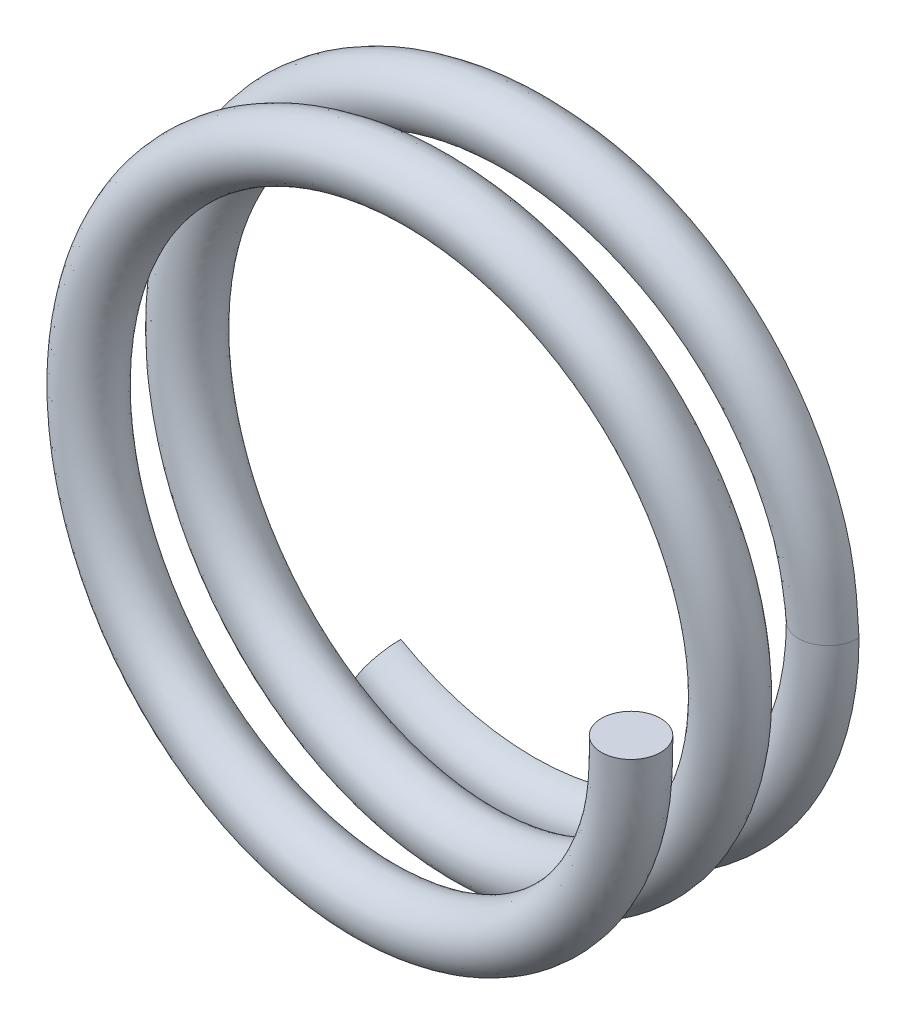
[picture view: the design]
ISO-10303-21;
HEADER;
FILE_DESCRIPTION(('STEP AP214'),'2;1');
FILE_NAME('part.step','',(''),(''),'','','');
FILE_SCHEMA(('AUTOMOTIVE_DESIGN { 1 0 10303 214 1 1 1 1 }'));
ENDSEC;
DATA;
#1=APPLICATION_CONTEXT('core data for automotive mechanical design processes');
#2=APPLICATION_PROTOCOL_DEFINITION('international standard','automotive_design',2000,#1);
#3=PRODUCT_CONTEXT('',#1,'mechanical');
#4=PRODUCT('Part','Part','',(#3));
#5=PRODUCT_RELATED_PRODUCT_CATEGORY('part','',(#4));
#6=PRODUCT_DEFINITION_FORMATION('','',#4);
#7=PRODUCT_DEFINITION_CONTEXT('part definition',#1,'design');
#8=PRODUCT_DEFINITION('design','',#6,#7);
#9=PRODUCT_DEFINITION_SHAPE('','',#8);
#10=(LENGTH_UNIT() NAMED_UNIT(*) SI_UNIT(.MILLI.,.METRE.));
#11=(NAMED_UNIT(*) PLANE_ANGLE_UNIT() SI_UNIT($,.RADIAN.));
#12=(NAMED_UNIT(*) SI_UNIT($,.STERADIAN.) SOLID_ANGLE_UNIT());
#13=UNCERTAINTY_MEASURE_WITH_UNIT(LENGTH_MEASURE(1.E-05),#10,'distance_accuracy_value','');
#14=(GEOMETRIC_REPRESENTATION_CONTEXT(3) GLOBAL_UNCERTAINTY_ASSIGNED_CONTEXT((#13)) GLOBAL_UNIT_ASSIGNED_CONTEXT((#10,
#11,#12)) REPRESENTATION_CONTEXT('',''));
#15=CARTESIAN_POINT('',(0.,0.,0.));
#16=DIRECTION('',(0.,0.,1.));
#17=DIRECTION('',(1.,0.,0.));
#18=AXIS2_PLACEMENT_3D('',#15,#16,#17);
#19=CARTESIAN_POINT('',(15.,0.,1.5));
#20=CARTESIAN_POINT('',(14.9434686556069,0.980039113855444,1.55199637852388));
#21=CARTESIAN_POINT('',(14.8302225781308,2.94329660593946,1.65615781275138));
#22=CARTESIAN_POINT('',(13.9418455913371,5.77650274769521,1.81245356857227));
#23=CARTESIAN_POINT('',(12.5535226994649,8.38759891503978,1.96879275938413));
#24=CARTESIAN_POINT('',(10.4671696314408,10.9271623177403,2.14223062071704));
#25=CARTESIAN_POINT('',(7.58613571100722,13.1398555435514,2.33334011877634));
#26=CARTESIAN_POINT('',(3.92662071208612,14.6543917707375,2.54166504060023));
#27=CARTESIAN_POINT('',(4.11401899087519E-05,15.1715918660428,2.75000784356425));
#28=CARTESIAN_POINT('',(-3.92693257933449,14.6556022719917,2.95833111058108));
#29=CARTESIAN_POINT('',(-7.58586251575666,13.1389788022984,3.1666585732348));
#30=CARTESIAN_POINT('',(-10.7277085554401,10.7277374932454,3.37500627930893));
#31=CARTESIAN_POINT('',(-13.1395863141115,7.58619905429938,3.58333901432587));
#32=CARTESIAN_POINT('',(-14.6551693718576,3.92680798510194,3.79165669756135));
#33=CARTESIAN_POINT('',(-15.1712462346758,-3.12971002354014E-05,3.99999979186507));
#34=CARTESIAN_POINT('',(-14.6548300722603,-3.92669076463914,4.20834340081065));
#35=CARTESIAN_POINT('',(-13.1398206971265,-7.58627068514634,4.41666146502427));
#36=CARTESIAN_POINT('',(-10.7278130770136,-10.7278977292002,4.62499295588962));
#37=CARTESIAN_POINT('',(-7.58571450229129,-13.1387744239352,4.83334182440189));
#38=CARTESIAN_POINT('',(-3.92696085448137,-14.6554610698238,5.04166963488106));
#39=CARTESIAN_POINT('',(4.36291658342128E-05,-15.1719571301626,5.24998976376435));
#40=CARTESIAN_POINT('',(3.92661725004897,-14.6542791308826,5.45833563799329));
#41=CARTESIAN_POINT('',(7.5859316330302,-13.1393329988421,5.66667583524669));
#42=CARTESIAN_POINT('',(10.7285480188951,-10.7285399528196,5.87499262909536));
#43=CARTESIAN_POINT('',(13.1388208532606,-7.58563797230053,6.08332834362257));
#44=CARTESIAN_POINT('',(14.6545092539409,-3.92671133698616,6.29167635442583));
#45=CARTESIAN_POINT('',(15.1725636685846,-3.08605043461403E-05,6.50000018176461));
#46=CARTESIAN_POINT('',(14.6547973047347,3.92679649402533,6.70832353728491));
#47=CARTESIAN_POINT('',(13.1386860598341,7.58562008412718,6.91667133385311));
#48=CARTESIAN_POINT('',(10.7283643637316,10.7282883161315,7.12500762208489));
#49=CARTESIAN_POINT('',(7.58613817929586,13.1396144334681,7.33332434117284));
#50=CARTESIAN_POINT('',(3.92657585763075,14.6543562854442,7.54166400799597));
#51=CARTESIAN_POINT('',(5.35997314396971E-05,15.1716155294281,7.75001022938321));
#52=CARTESIAN_POINT('',(-3.92693805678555,14.6556080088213,7.95833071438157));
#53=CARTESIAN_POINT('',(-7.58585858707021,13.1389737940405,8.16665797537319));
#54=CARTESIAN_POINT('',(-10.7277098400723,10.7277381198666,8.37500677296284));
#55=CARTESIAN_POINT('',(-13.1395867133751,7.58619950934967,8.5833388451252));
#56=CARTESIAN_POINT('',(-14.6551692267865,3.92680794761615,8.79165668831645));
#57=CARTESIAN_POINT('',(-15.1712461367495,-3.14499375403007E-05,8.9999998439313));
#58=CARTESIAN_POINT('',(-14.654829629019,-3.92669054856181,9.20834339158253));
#59=CARTESIAN_POINT('',(-13.1398232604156,-7.58627176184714,9.41666129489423));
#60=CARTESIAN_POINT('',(-10.7278077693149,-10.7278945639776,9.62499345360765));
#61=CARTESIAN_POINT('',(-7.58571958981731,-13.1387763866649,9.83334122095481));
#62=CARTESIAN_POINT('',(-3.92696098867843,-14.655487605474,10.041669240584));
#63=CARTESIAN_POINT('',(2.9082075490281E-05,-15.171864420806,10.2499921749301));
#64=CARTESIAN_POINT('',(3.92668405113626,-14.6543878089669,10.4583345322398));
#65=CARTESIAN_POINT('',(7.58592254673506,-13.1395893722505,10.6666601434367));
#66=CARTESIAN_POINT('',(10.4672636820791,-10.9272676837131,10.8577695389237));
#67=CARTESIAN_POINT('',(12.553480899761,-8.38754549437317,11.0312069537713));
#68=CARTESIAN_POINT('',(13.9422248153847,-5.77671048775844,11.187546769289));
#69=CARTESIAN_POINT('',(14.8299103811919,-2.94320033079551,11.3438418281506));
#70=CARTESIAN_POINT('',(14.9432613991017,-0.980005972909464,11.4480035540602));
#71=CARTESIAN_POINT('',(14.9998450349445,4.25082742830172E-10,11.4999999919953));
#72=CARTESIAN_POINT('',(18.,0.,1.5));
#73=CARTESIAN_POINT('',(17.9323063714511,1.17617130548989,1.55193830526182));
#74=CARTESIAN_POINT('',(17.7966995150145,3.53232943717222,1.6559834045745));
#75=CARTESIAN_POINT('',(16.7304312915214,6.93069596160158,1.81304095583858));
#76=CARTESIAN_POINT('',(15.0648037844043,10.0648097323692,1.96888233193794));
#77=CARTESIAN_POINT('',(12.5582750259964,13.1148525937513,2.14252497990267));
#78=CARTESIAN_POINT('',(9.10608570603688,15.7659272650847,2.33316062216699));
#79=CARTESIAN_POINT('',(4.71216641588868,17.5858635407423,2.54183736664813));
#80=CARTESIAN_POINT('',(-0.00209417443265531,18.2059563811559,2.75042629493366));
#81=CARTESIAN_POINT('',(-4.71136257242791,17.5866699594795,2.958385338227));
#82=CARTESIAN_POINT('',(-9.10182717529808,15.7677965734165,3.16657352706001));
#83=CARTESIAN_POINT('',(-12.8743834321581,12.8727598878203,3.37533635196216));
#84=CARTESIAN_POINT('',(-15.7680538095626,9.10199791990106,3.58373251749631));
#85=CARTESIAN_POINT('',(-17.5855251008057,4.71436549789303,3.7914596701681));
#86=CARTESIAN_POINT('',(-18.2060659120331,-2.21536066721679E-05,4.00015466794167));
#87=CARTESIAN_POINT('',(-17.5851902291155,-4.71423300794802,4.20884973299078));
#88=CARTESIAN_POINT('',(-15.7682950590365,-9.10205608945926,4.41658110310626));
#89=CARTESIAN_POINT('',(-12.8745053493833,-12.8729042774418,4.62496853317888));
#90=CARTESIAN_POINT('',(-9.10167577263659,-15.7675961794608,4.83373398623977));
#91=CARTESIAN_POINT('',(-4.71143842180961,-17.5864986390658,5.04195919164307));
#92=CARTESIAN_POINT('',(-0.0021430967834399,-18.2063741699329,5.24981036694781));
#93=CARTESIAN_POINT('',(4.7124657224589,-17.5855720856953,5.45855207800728));
#94=CARTESIAN_POINT('',(9.1049848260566,-15.7659968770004,5.66717218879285));
#95=CARTESIAN_POINT('',(12.8726878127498,-12.8754697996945,5.8748441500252));
#96=CARTESIAN_POINT('',(15.7665939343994,-9.10371710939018,6.08336225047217));
#97=CARTESIAN_POINT('',(17.5861149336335,-4.71026018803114,6.29212393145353));
#98=CARTESIAN_POINT('',(18.2067610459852,-3.84891972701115E-05,6.50015514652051));
#99=CARTESIAN_POINT('',(17.5864072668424,4.71032890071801,6.70818589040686));
#100=CARTESIAN_POINT('',(15.7664681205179,9.10368379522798,6.91694735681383));
#101=CARTESIAN_POINT('',(12.8725152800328,12.875207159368,7.12546603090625));
#102=CARTESIAN_POINT('',(9.1052051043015,15.7662702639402,7.33313791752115));
#103=CARTESIAN_POINT('',(4.71244168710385,17.5856445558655,7.54175749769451));
#104=CARTESIAN_POINT('',(-0.00211652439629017,18.2060326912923,7.75049955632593));
#105=CARTESIAN_POINT('',(-4.71140083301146,17.5866495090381,7.95835108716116));
#106=CARTESIAN_POINT('',(-9.10180477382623,15.7678041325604,8.16657574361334));
#107=CARTESIAN_POINT('',(-12.8743897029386,12.872757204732,8.37534112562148));
#108=CARTESIAN_POINT('',(-15.7680534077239,9.10199831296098,8.58372913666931));
#109=CARTESIAN_POINT('',(-17.5855250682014,4.71436584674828,8.791460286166));
#110=CARTESIAN_POINT('',(-18.2060658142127,-2.25735037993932E-05,9.00015489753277));
#111=CARTESIAN_POINT('',(-17.5851896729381,-4.71423240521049,9.20885034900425));
#112=CARTESIAN_POINT('',(-15.7682984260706,-9.10205722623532,9.41657772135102));
#113=CARTESIAN_POINT('',(-12.8744950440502,-12.8729044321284,9.62497331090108));
#114=CARTESIAN_POINT('',(-9.10169935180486,-15.7675855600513,9.83373619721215));
#115=CARTESIAN_POINT('',(-4.71140576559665,-17.5865513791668,10.0419249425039));
#116=CARTESIAN_POINT('',(-0.00212275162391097,-18.2062287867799,10.2498836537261));
#117=CARTESIAN_POINT('',(4.71221213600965,-17.5858643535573,10.4584721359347));
#118=CARTESIAN_POINT('',(9.10585910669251,-15.7656689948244,10.6671495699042));
#119=CARTESIAN_POINT('',(12.5583574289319,-13.114968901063,10.8577851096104));
#120=CARTESIAN_POINT('',(15.0647522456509,-10.0647709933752,11.0314273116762));
#121=CARTESIAN_POINT('',(16.7308047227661,-6.9309177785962,11.1872693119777));
#122=CARTESIAN_POINT('',(17.7963837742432,-3.53225069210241,11.3443261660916));
#123=CARTESIAN_POINT('',(17.9320979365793,-1.17615475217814,11.4483715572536));
#124=CARTESIAN_POINT('',(17.99984501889,-1.64418778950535E-05,11.5003099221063));
#125=CARTESIAN_POINT('',(18.,0.,-1.5));
#126=CARTESIAN_POINT('',(17.9322539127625,1.17614724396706,-1.44806169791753));
#127=CARTESIAN_POINT('',(17.7965419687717,3.53225717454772,-1.34401660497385));
#128=CARTESIAN_POINT('',(16.7309520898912,6.93096946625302,-1.18695900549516));
#129=CARTESIAN_POINT('',(15.0648944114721,10.0648383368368,-1.03111766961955));
#130=CARTESIAN_POINT('',(12.5584754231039,13.1150736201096,-0.857475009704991));
#131=CARTESIAN_POINT('',(9.10594614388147,15.7657987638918,-0.666839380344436));
#132=CARTESIAN_POINT('',(4.71227811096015,17.5860086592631,-0.458162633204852));
#133=CARTESIAN_POINT('',(-0.00210690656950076,18.2063865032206,-0.249573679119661));
#134=CARTESIAN_POINT('',(-4.71143793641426,17.5867047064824,-0.0416146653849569));
#135=CARTESIAN_POINT('',(-9.10175901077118,15.7677312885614,0.166573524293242));
#136=CARTESIAN_POINT('',(-12.8745903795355,12.873031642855,0.375336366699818));
#137=CARTESIAN_POINT('',(-15.7684298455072,9.10214392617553,0.583732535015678));
#138=CARTESIAN_POINT('',(-17.5853365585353,4.71428665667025,0.791459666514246));
#139=CARTESIAN_POINT('',(-18.2062225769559,4.75475799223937E-05,1.0001546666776));
#140=CARTESIAN_POINT('',(-17.5856809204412,-4.71439295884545,1.20884976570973));
#141=CARTESIAN_POINT('',(-15.7681935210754,-9.10206822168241,1.41658109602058));
#142=CARTESIAN_POINT('',(-12.874516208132,-12.8728515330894,1.62496852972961));
#143=CARTESIAN_POINT('',(-9.1019016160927,-15.7679300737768,1.83373400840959));
#144=CARTESIAN_POINT('',(-4.71144975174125,-17.5867989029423,2.04195919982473));
#145=CARTESIAN_POINT('',(-0.00213308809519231,-18.206188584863,2.24981036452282));
#146=CARTESIAN_POINT('',(4.71245845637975,-17.5858025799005,2.45855208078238));
#147=CARTESIAN_POINT('',(9.10527327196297,-15.7664127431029,2.66717221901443));
#148=CARTESIAN_POINT('',(12.8726180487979,-12.8753251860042,2.87484414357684));
#149=CARTESIAN_POINT('',(15.7665915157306,-9.10378273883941,3.08336224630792));
#150=CARTESIAN_POINT('',(17.5865546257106,-4.71038774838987,3.29212395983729));
#151=CARTESIAN_POINT('',(18.2069177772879,3.01427640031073E-05,3.50015514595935));
#152=CARTESIAN_POINT('',(17.5862704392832,4.71028228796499,3.70818588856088));
#153=CARTESIAN_POINT('',(15.7667420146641,9.10377499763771,3.9169473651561));
#154=CARTESIAN_POINT('',(12.8728065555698,12.875573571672,4.12546605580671));
#155=CARTESIAN_POINT('',(9.10507359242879,15.7661257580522,4.33313791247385));
#156=CARTESIAN_POINT('',(4.71253014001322,17.585716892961,4.54175749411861));
#157=CARTESIAN_POINT('',(-0.00212675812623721,18.2065317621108,4.75049958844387));
#158=CARTESIAN_POINT('',(-4.71147054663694,17.586652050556,4.9583510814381));
#159=CARTESIAN_POINT('',(-9.10173554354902,15.7677418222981,5.16657574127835));
#160=CARTESIAN_POINT('',(-12.8746006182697,12.8730315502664,5.37534114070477));
#161=CARTESIAN_POINT('',(-15.7684264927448,9.10214277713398,5.58372915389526));
#162=CARTESIAN_POINT('',(-17.5853371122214,4.71428725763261,5.7914602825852));
#163=CARTESIAN_POINT('',(-18.2062226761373,4.71276689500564E-05,6.00015489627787));
#164=CARTESIAN_POINT('',(-17.5856809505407,-4.71439260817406,6.20885038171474));
#165=CARTESIAN_POINT('',(-15.7681939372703,-9.10206781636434,6.41657771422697));
#166=CARTESIAN_POINT('',(-12.8745098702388,-12.8728542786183,6.62497330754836));
#167=CARTESIAN_POINT('',(-9.10192413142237,-15.7679224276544,6.83373621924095));
#168=CARTESIAN_POINT('',(-4.71141144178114,-17.5868194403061,7.04192494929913));
#169=CARTESIAN_POINT('',(-0.00211024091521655,-18.2061121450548,7.249883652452));
#170=CARTESIAN_POINT('',(4.71218159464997,-17.5860220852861,7.45847213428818));
#171=CARTESIAN_POINT('',(9.10615569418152,-15.7660687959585,7.66714960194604));
#172=CARTESIAN_POINT('',(12.5583730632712,-13.1149738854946,7.85778510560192));
#173=CARTESIAN_POINT('',(15.0649210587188,-10.0649156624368,8.0314273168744));
#174=CARTESIAN_POINT('',(16.7305720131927,-6.93076351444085,8.18726930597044));
#175=CARTESIAN_POINT('',(17.7968477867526,-3.53238380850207,8.34432619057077));
#176=CARTESIAN_POINT('',(17.9324591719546,-1.17619907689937,8.44837157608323));
#177=CARTESIAN_POINT('',(18.000154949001,-1.64427272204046E-05,8.50030993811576));
#178=CARTESIAN_POINT('',(15.,0.,-1.5));
#179=CARTESIAN_POINT('',(14.9434161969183,0.980015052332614,-1.44800362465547));
#180=CARTESIAN_POINT('',(14.830065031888,2.94322434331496,-1.34384219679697));
#181=CARTESIAN_POINT('',(13.9423663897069,5.77677625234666,-1.18754639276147));
#182=CARTESIAN_POINT('',(12.5536133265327,8.38762751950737,-1.03120724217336));
#183=CARTESIAN_POINT('',(10.4673700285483,10.9273833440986,-0.857769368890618));
#184=CARTESIAN_POINT('',(7.58599614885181,13.1397270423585,-0.666659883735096));
#185=CARTESIAN_POINT('',(3.92673240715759,14.6545368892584,-0.458334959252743));
#186=CARTESIAN_POINT('',(2.84080530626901E-05,15.1720219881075,-0.249992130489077));
#187=CARTESIAN_POINT('',(-3.92700794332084,14.6556370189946,-0.0416688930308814));
#188=CARTESIAN_POINT('',(-7.58579435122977,13.1389135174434,0.166658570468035));
#189=CARTESIAN_POINT('',(-10.7279155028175,10.7280092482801,0.375006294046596));
#190=CARTESIAN_POINT('',(-13.1399623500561,7.58634506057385,0.58333903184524));
#191=CARTESIAN_POINT('',(-14.6549808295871,3.92672914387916,0.791656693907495));
#192=CARTESIAN_POINT('',(-15.1714028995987,3.8404086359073E-05,0.999999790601));
#193=CARTESIAN_POINT('',(-14.655320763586,-3.92685071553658,1.2083434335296));
#194=CARTESIAN_POINT('',(-13.1397191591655,-7.58628281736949,1.41666145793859));
#195=CARTESIAN_POINT('',(-10.7278239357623,-10.7278449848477,1.62499295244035));
#196=CARTESIAN_POINT('',(-7.58594034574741,-13.1391083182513,1.83334184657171));
#197=CARTESIAN_POINT('',(-3.926972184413,-14.6557613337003,2.04166964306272));
#198=CARTESIAN_POINT('',(5.36378540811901E-05,-15.1717715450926,2.24998976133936));
#199=CARTESIAN_POINT('',(3.92660998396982,-14.6545096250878,2.45833564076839));
#200=CARTESIAN_POINT('',(7.58622007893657,-13.1397488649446,2.66667586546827));
#201=CARTESIAN_POINT('',(10.7284782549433,-10.7283953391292,2.87499262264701));
#202=CARTESIAN_POINT('',(13.1388184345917,-7.58570360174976,3.08332833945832));
#203=CARTESIAN_POINT('',(14.654948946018,-3.9268388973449,3.2916763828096));
#204=CARTESIAN_POINT('',(15.1727203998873,3.77714569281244E-05,3.50000018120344));
#205=CARTESIAN_POINT('',(14.6546604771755,3.92674988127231,3.70832353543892));
#206=CARTESIAN_POINT('',(13.1389599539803,7.58571128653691,3.91667134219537));
#207=CARTESIAN_POINT('',(10.7286556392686,10.7286547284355,4.12500764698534));
#208=CARTESIAN_POINT('',(7.58600666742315,13.13946992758,4.33332433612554));
#209=CARTESIAN_POINT('',(3.92666431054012,14.6544286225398,4.54166400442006));
#210=CARTESIAN_POINT('',(4.33660014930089E-05,15.1721146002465,4.75001026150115));
#211=CARTESIAN_POINT('',(-3.92700777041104,14.6556105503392,4.95833070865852));
#212=CARTESIAN_POINT('',(-7.585789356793,13.1389114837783,5.1666579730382));
#213=CARTESIAN_POINT('',(-10.7279207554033,10.728012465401,5.37500678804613));
#214=CARTESIAN_POINT('',(-13.1399597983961,7.58634397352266,5.58333886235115));
#215=CARTESIAN_POINT('',(-14.6549812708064,3.92672935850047,5.79165668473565));
#216=CARTESIAN_POINT('',(-15.1714029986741,3.82512352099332E-05,5.9999998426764));
#217=CARTESIAN_POINT('',(-14.6553209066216,-3.92685075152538,6.20834342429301));
#218=CARTESIAN_POINT('',(-13.1397187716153,-7.58628235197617,6.41666128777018));
#219=CARTESIAN_POINT('',(-10.7278225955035,-10.7278444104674,6.62499345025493));
#220=CARTESIAN_POINT('',(-7.58594436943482,-13.139113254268,6.83334124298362));
#221=CARTESIAN_POINT('',(-3.92696666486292,-14.6557556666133,7.04166924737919));
#222=CARTESIAN_POINT('',(4.15927841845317E-05,-15.171747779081,7.24999217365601));
#223=CARTESIAN_POINT('',(3.92665350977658,-14.6545455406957,7.45833453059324));
#224=CARTESIAN_POINT('',(7.58621913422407,-13.1399891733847,7.6666601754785));
#225=CARTESIAN_POINT('',(10.4672793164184,-10.9272726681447,7.85776953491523));
#226=CARTESIAN_POINT('',(12.5536497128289,-8.38769016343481,8.03120695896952));
#227=CARTESIAN_POINT('',(13.9419921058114,-5.77655622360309,8.1875467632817));
#228=CARTESIAN_POINT('',(14.8303743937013,-2.94333344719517,8.34384185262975));
#229=CARTESIAN_POINT('',(14.943622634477,-0.980050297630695,8.44800357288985));
#230=CARTESIAN_POINT('',(15.0001549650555,-4.24242608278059E-10,8.50000000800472));
#231=CARTESIAN_POINT('',(12.,0.,-1.5));
#232=CARTESIAN_POINT('',(11.9545784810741,0.783882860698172,-1.44794555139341));
#233=CARTESIAN_POINT('',(11.8635880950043,2.35419151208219,-1.34366778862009));
#234=CARTESIAN_POINT('',(11.1537806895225,4.6225830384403,-1.18813378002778));
#235=CARTESIAN_POINT('',(10.0423322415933,6.71041670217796,-1.03129681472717));
#236=CARTESIAN_POINT('',(8.37626463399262,8.73969306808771,-0.858063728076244));
#237=CARTESIAN_POINT('',(6.06604615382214,10.5136553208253,-0.666480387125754));
#238=CARTESIAN_POINT('',(3.14118670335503,11.7230651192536,-0.458507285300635));
#239=CARTESIAN_POINT('',(0.00216372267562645,12.1376574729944,-0.250410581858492));
#240=CARTESIAN_POINT('',(-3.14257795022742,11.7245693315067,-0.041723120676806));
#241=CARTESIAN_POINT('',(-6.06982969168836,10.5100957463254,0.166743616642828));
#242=CARTESIAN_POINT('',(-8.5812406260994,8.58298685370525,0.374676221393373));
#243=CARTESIAN_POINT('',(-10.5114948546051,6.07054619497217,0.582945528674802));
#244=CARTESIAN_POINT('',(-11.724625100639,3.13917163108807,0.791853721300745));
#245=CARTESIAN_POINT('',(-12.1365832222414,2.92605927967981E-05,0.999844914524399));
#246=CARTESIAN_POINT('',(-11.7249606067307,-3.13930847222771,1.20783710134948));
#247=CARTESIAN_POINT('',(-10.5112447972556,-6.07049741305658,1.4167418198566));
#248=CARTESIAN_POINT('',(-8.58113166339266,-8.58283843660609,1.62501737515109));
#249=CARTESIAN_POINT('',(-6.06997907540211,-10.5102865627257,1.83294968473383));
#250=CARTESIAN_POINT('',(-3.14249461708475,-11.7247237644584,2.04138008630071));
#251=CARTESIAN_POINT('',(0.00224036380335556,-12.1373545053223,2.25016915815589));
#252=CARTESIAN_POINT('',(3.14076151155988,-11.7232166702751,2.45811920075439));
#253=CARTESIAN_POINT('',(6.06716688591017,-10.5130849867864,2.6661795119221));
#254=CARTESIAN_POINT('',(8.58433846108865,-8.58146549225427,2.87514110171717));
#255=CARTESIAN_POINT('',(10.5110453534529,-6.06762446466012,3.08329443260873));
#256=CARTESIAN_POINT('',(11.7233432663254,-3.14329004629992,3.2912288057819));
#257=CARTESIAN_POINT('',(12.1385230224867,4.54001498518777E-05,3.49984521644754));
#258=CARTESIAN_POINT('',(11.7230505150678,3.14321747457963,3.70846118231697));
#259=CARTESIAN_POINT('',(10.5111778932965,6.06764757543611,3.91639531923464));
#260=CARTESIAN_POINT('',(8.58450472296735,8.58173588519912,4.12454923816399));
#261=CARTESIAN_POINT('',(6.06693974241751,10.5128140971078,4.33351075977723));
#262=CARTESIAN_POINT('',(3.14079848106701,11.7231403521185,4.54157051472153));
#263=CARTESIAN_POINT('',(0.00221349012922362,12.1376974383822,4.74952093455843));
#264=CARTESIAN_POINT('',(-3.14254499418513,11.7245690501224,4.95831033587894));
#265=CARTESIAN_POINT('',(-6.06984317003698,10.5100811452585,5.16674020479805));
#266=CARTESIAN_POINT('',(-8.58124089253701,8.58299338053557,5.37467243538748));
#267=CARTESIAN_POINT('',(-10.5114931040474,6.07054516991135,5.58294857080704));
#268=CARTESIAN_POINT('',(-11.7246254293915,3.13917145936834,5.79185308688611));
#269=CARTESIAN_POINT('',(-12.136583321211,2.93748014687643E-05,5.99984478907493));
#270=CARTESIAN_POINT('',(-11.7249608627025,-3.1393088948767,6.20783646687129));
#271=CARTESIAN_POINT('',(-10.5112436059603,-6.07049688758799,6.41674486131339));
#272=CARTESIAN_POINT('',(-8.58113532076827,-8.58283454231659,6.6250135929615));
#273=CARTESIAN_POINT('',(-6.06996460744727,-10.5103040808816,6.83294626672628));
#274=CARTESIAN_POINT('',(-3.14252188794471,-11.7246918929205,7.04141354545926));
#275=CARTESIAN_POINT('',(0.0021934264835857,-12.1373834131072,7.25010069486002));
#276=CARTESIAN_POINT('',(3.14112542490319,-11.7230689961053,7.45819692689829));
#277=CARTESIAN_POINT('',(6.06628257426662,-10.5139095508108,7.66617074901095));
#278=CARTESIAN_POINT('',(8.37618556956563,-8.7395714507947,7.85775396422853));
#279=CARTESIAN_POINT('',(10.042378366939,-6.71046466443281,8.03098660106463));
#280=CARTESIAN_POINT('',(11.15341219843,-4.62234893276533,8.18782422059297));
#281=CARTESIAN_POINT('',(11.8639010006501,-2.35428308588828,8.34335751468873));
#282=CARTESIAN_POINT('',(11.9547860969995,-0.783901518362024,8.44763556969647));
#283=CARTESIAN_POINT('',(12.00015498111,1.6441878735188E-05,8.49969007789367));
#284=CARTESIAN_POINT('',(12.,0.,1.5));
#285=CARTESIAN_POINT('',(11.9546309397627,0.783906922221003,1.55205445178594));
#286=CARTESIAN_POINT('',(11.8637456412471,2.35426377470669,1.65633222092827));
#287=CARTESIAN_POINT('',(11.1532598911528,4.62230953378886,1.81186618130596));
#288=CARTESIAN_POINT('',(10.0422416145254,6.71038809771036,1.96870318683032));
#289=CARTESIAN_POINT('',(8.37606423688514,8.73947204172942,2.14193626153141));
#290=CARTESIAN_POINT('',(6.06618571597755,10.5137838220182,2.33351961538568));
#291=CARTESIAN_POINT('',(3.14107500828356,11.7229200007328,2.54149271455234));
#292=CARTESIAN_POINT('',(0.00217645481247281,12.1372273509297,2.74958939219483));
#293=CARTESIAN_POINT('',(-3.14250258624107,11.7245345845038,2.95827688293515));
#294=CARTESIAN_POINT('',(-6.06989785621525,10.5101610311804,3.16674361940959));
#295=CARTESIAN_POINT('',(-8.581033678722,8.58271509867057,3.37467620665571));
#296=CARTESIAN_POINT('',(-10.5111188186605,6.07040018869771,3.58294551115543));
#297=CARTESIAN_POINT('',(-11.7248136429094,3.13925047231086,3.7918537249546));
#298=CARTESIAN_POINT('',(-12.1364265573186,-4.04405937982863E-05,3.99984491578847));
#299=CARTESIAN_POINT('',(-11.7244699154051,-3.13914852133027,4.20783706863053));
#300=CARTESIAN_POINT('',(-10.5113463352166,-6.07048528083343,4.41674182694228));
#301=CARTESIAN_POINT('',(-8.58112080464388,-8.58289118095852,4.62501737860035));
#302=CARTESIAN_POINT('',(-6.069753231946,-10.5099526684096,4.83294966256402));
#303=CARTESIAN_POINT('',(-3.14248328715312,-11.7244235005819,5.04138007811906));
#304=CARTESIAN_POINT('',(0.00223035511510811,-12.1375400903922,5.25016916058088));
#305=CARTESIAN_POINT('',(3.14076877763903,-11.7229861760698,5.4581191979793));
#306=CARTESIAN_POINT('',(6.0668784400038,-10.5126691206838,5.66617948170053));
#307=CARTESIAN_POINT('',(8.58440822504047,-8.5816101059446,5.87514110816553));
#308=CARTESIAN_POINT('',(10.5110477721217,-6.06755883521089,6.08329443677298));
#309=CARTESIAN_POINT('',(11.7229035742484,-3.14316248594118,6.29122877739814));
#310=CARTESIAN_POINT('',(12.138366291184,-2.32318114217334E-05,6.4998452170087));
#311=CARTESIAN_POINT('',(11.723187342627,3.14326408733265,6.70846118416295));
#312=CARTESIAN_POINT('',(10.5109039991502,6.06755637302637,6.91639531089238));
#313=CARTESIAN_POINT('',(8.58421344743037,8.58136947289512,7.12454921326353));
#314=CARTESIAN_POINT('',(6.06707125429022,10.5129586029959,7.33351076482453));
#315=CARTESIAN_POINT('',(3.14071002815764,11.723068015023,7.54157051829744));
#316=CARTESIAN_POINT('',(0.00222372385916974,12.1371983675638,7.74952090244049));
#317=CARTESIAN_POINT('',(-3.14247528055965,11.7245665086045,7.95831034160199));
#318=CARTESIAN_POINT('',(-6.0699124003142,10.5101434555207,8.16674020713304));
#319=CARTESIAN_POINT('',(-8.58102997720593,8.58271903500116,8.3746724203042));
#320=CARTESIAN_POINT('',(-10.5111200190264,6.07040070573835,8.58294855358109));
#321=CARTESIAN_POINT('',(-11.7248133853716,3.13925004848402,8.79185309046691));
#322=CARTESIAN_POINT('',(-12.1364264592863,-4.0326371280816E-05,8.99984479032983));
#323=CARTESIAN_POINT('',(-11.7244695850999,-3.13914869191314,9.2078364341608));
#324=CARTESIAN_POINT('',(-10.5113480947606,-6.07048629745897,9.41674486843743));
#325=CARTESIAN_POINT('',(-8.58112049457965,-8.58288469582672,9.62501359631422));
#326=CARTESIAN_POINT('',(-6.06973982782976,-10.5099672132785,9.83294624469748));
#327=CARTESIAN_POINT('',(-3.14251621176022,-11.7244238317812,10.0414135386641));
#328=CARTESIAN_POINT('',(0.00218091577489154,-12.1375000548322,10.2501006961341));
#329=CARTESIAN_POINT('',(3.14115596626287,-11.7229112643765,10.4581969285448));
#330=CARTESIAN_POINT('',(6.06598598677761,-10.5135097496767,10.6661707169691));
#331=CARTESIAN_POINT('',(8.37616993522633,-8.7395664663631,10.857753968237));
#332=CARTESIAN_POINT('',(10.0422095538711,-6.71031999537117,11.0309865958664));
#333=CARTESIAN_POINT('',(11.1536449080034,-4.62250319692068,11.1878242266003));
#334=CARTESIAN_POINT('',(11.8634369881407,-2.35414996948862,11.3433574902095));
#335=CARTESIAN_POINT('',(11.9544248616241,-0.783857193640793,11.4476355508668));
#336=CARTESIAN_POINT('',(11.999845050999,1.64427280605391E-05,11.4996900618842));
#337=CARTESIAN_POINT('',(15.,0.,1.5));
#338=CARTESIAN_POINT('',(14.9434686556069,0.980039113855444,1.55199637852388));
#339=CARTESIAN_POINT('',(14.8302225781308,2.94329660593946,1.65615781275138));
#340=CARTESIAN_POINT('',(13.9418455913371,5.77650274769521,1.81245356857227));
#341=CARTESIAN_POINT('',(12.5535226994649,8.38759891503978,1.96879275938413));
#342=CARTESIAN_POINT('',(10.4671696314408,10.9271623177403,2.14223062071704));
#343=CARTESIAN_POINT('',(7.58613571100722,13.1398555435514,2.33334011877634));
#344=CARTESIAN_POINT('',(3.92662071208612,14.6543917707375,2.54166504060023));
#345=CARTESIAN_POINT('',(4.11401899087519E-05,15.1715918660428,2.75000784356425));
#346=CARTESIAN_POINT('',(-3.92693257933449,14.6556022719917,2.95833111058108));
#347=CARTESIAN_POINT('',(-7.58586251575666,13.1389788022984,3.1666585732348));
#348=CARTESIAN_POINT('',(-10.7277085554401,10.7277374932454,3.37500627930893));
#349=CARTESIAN_POINT('',(-13.1395863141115,7.58619905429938,3.58333901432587));
#350=CARTESIAN_POINT('',(-14.6551693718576,3.92680798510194,3.79165669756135));
#351=CARTESIAN_POINT('',(-15.1712462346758,-3.12971002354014E-05,3.99999979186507));
#352=CARTESIAN_POINT('',(-14.6548300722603,-3.92669076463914,4.20834340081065));
#353=CARTESIAN_POINT('',(-13.1398206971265,-7.58627068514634,4.41666146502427));
#354=CARTESIAN_POINT('',(-10.7278130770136,-10.7278977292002,4.62499295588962));
#355=CARTESIAN_POINT('',(-7.58571450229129,-13.1387744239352,4.83334182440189));
#356=CARTESIAN_POINT('',(-3.92696085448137,-14.6554610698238,5.04166963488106));
#357=CARTESIAN_POINT('',(4.36291658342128E-05,-15.1719571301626,5.24998976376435));
#358=CARTESIAN_POINT('',(3.92661725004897,-14.6542791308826,5.45833563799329));
#359=CARTESIAN_POINT('',(7.5859316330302,-13.1393329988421,5.66667583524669));
#360=CARTESIAN_POINT('',(10.7285480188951,-10.7285399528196,5.87499262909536));
#361=CARTESIAN_POINT('',(13.1388208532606,-7.58563797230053,6.08332834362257));
#362=CARTESIAN_POINT('',(14.6545092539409,-3.92671133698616,6.29167635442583));
#363=CARTESIAN_POINT('',(15.1725636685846,-3.08605043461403E-05,6.50000018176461));
#364=CARTESIAN_POINT('',(14.6547973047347,3.92679649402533,6.70832353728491));
#365=CARTESIAN_POINT('',(13.1386860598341,7.58562008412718,6.91667133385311));
#366=CARTESIAN_POINT('',(10.7283643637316,10.7282883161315,7.12500762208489));
#367=CARTESIAN_POINT('',(7.58613817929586,13.1396144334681,7.33332434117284));
#368=CARTESIAN_POINT('',(3.92657585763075,14.6543562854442,7.54166400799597));
#369=CARTESIAN_POINT('',(5.35997314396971E-05,15.1716155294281,7.75001022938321));
#370=CARTESIAN_POINT('',(-3.92693805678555,14.6556080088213,7.95833071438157));
#371=CARTESIAN_POINT('',(-7.58585858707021,13.1389737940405,8.16665797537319));
#372=CARTESIAN_POINT('',(-10.7277098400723,10.7277381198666,8.37500677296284));
#373=CARTESIAN_POINT('',(-13.1395867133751,7.58619950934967,8.5833388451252));
#374=CARTESIAN_POINT('',(-14.6551692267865,3.92680794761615,8.79165668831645));
#375=CARTESIAN_POINT('',(-15.1712461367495,-3.14499375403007E-05,8.9999998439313));
#376=CARTESIAN_POINT('',(-14.654829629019,-3.92669054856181,9.20834339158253));
#377=CARTESIAN_POINT('',(-13.1398232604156,-7.58627176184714,9.41666129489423));
#378=CARTESIAN_POINT('',(-10.7278077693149,-10.7278945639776,9.62499345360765));
#379=CARTESIAN_POINT('',(-7.58571958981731,-13.1387763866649,9.83334122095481));
#380=CARTESIAN_POINT('',(-3.92696098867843,-14.655487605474,10.041669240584));
#381=CARTESIAN_POINT('',(2.9082075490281E-05,-15.171864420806,10.2499921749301));
#382=CARTESIAN_POINT('',(3.92668405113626,-14.6543878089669,10.4583345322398));
#383=CARTESIAN_POINT('',(7.58592254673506,-13.1395893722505,10.6666601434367));
#384=CARTESIAN_POINT('',(10.4672636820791,-10.9272676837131,10.8577695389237));
#385=CARTESIAN_POINT('',(12.553480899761,-8.38754549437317,11.0312069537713));
#386=CARTESIAN_POINT('',(13.9422248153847,-5.77671048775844,11.187546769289));
#387=CARTESIAN_POINT('',(14.8299103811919,-2.94320033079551,11.3438418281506));
#388=CARTESIAN_POINT('',(14.9432613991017,-0.980005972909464,11.4480035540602));
#389=CARTESIAN_POINT('',(14.9998450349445,4.25082742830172E-10,11.4999999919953));
#390=(BOUNDED_SURFACE() B_SPLINE_SURFACE(3,3,((#19,#20,#21,#22,#23,#24,#25,#26,#27,#28,#29,#30,
#31,#32,#33,#34,#35,#36,#37,#38,#39,#40,#41,#42,#43,#44,#45,#46,#47,#48,#49,#50,#51,#52,#53,#54,
#55,#56,#57,#58,#59,#60,#61,#62,#63,#64,#65,#66,#67,#68,#69,#70,#71),(#72,#73,#74,#75,#76,#77,
#78,#79,#80,#81,#82,#83,#84,#85,#86,#87,#88,#89,#90,#91,#92,#93,#94,#95,#96,#97,#98,#99,#100,
#101,#102,#103,#104,#105,#106,#107,#108,#109,#110,#111,#112,#113,#114,#115,#116,#117,#118,#119,
#120,#121,#122,#123,#124),(#125,#126,#127,#128,#129,#130,#131,#132,#133,#134,#135,#136,#137,
#138,#139,#140,#141,#142,#143,#144,#145,#146,#147,#148,#149,#150,#151,#152,#153,#154,#155,#156,
#157,#158,#159,#160,#161,#162,#163,#164,#165,#166,#167,#168,#169,#170,#171,#172,#173,#174,#175,
#176,#177),(#178,#179,#180,#181,#182,#183,#184,#185,#186,#187,#188,#189,#190,#191,#192,#193,
#194,#195,#196,#197,#198,#199,#200,#201,#202,#203,#204,#205,#206,#207,#208,#209,#210,#211,#212,
#213,#214,#215,#216,#217,#218,#219,#220,#221,#222,#223,#224,#225,#226,#227,#228,#229,#230),
(#231,#232,#233,#234,#235,#236,#237,#238,#239,#240,#241,#242,#243,#244,#245,#246,#247,#248,#249,
#250,#251,#252,#253,#254,#255,#256,#257,#258,#259,#260,#261,#262,#263,#264,#265,#266,#267,#268,
#269,#270,#271,#272,#273,#274,#275,#276,#277,#278,#279,#280,#281,#282,#283),(#284,#285,#286,
#287,#288,#289,#290,#291,#292,#293,#294,#295,#296,#297,#298,#299,#300,#301,#302,#303,#304,#305,
#306,#307,#308,#309,#310,#311,#312,#313,#314,#315,#316,#317,#318,#319,#320,#321,#322,#323,#324,
#325,#326,#327,#328,#329,#330,#331,#332,#333,#334,#335,#336),(#337,#338,#339,#340,#341,#342,
#343,#344,#345,#346,#347,#348,#349,#350,#351,#352,#353,#354,#355,#356,#357,#358,#359,#360,#361,
#362,#363,#364,#365,#366,#367,#368,#369,#370,#371,#372,#373,#374,#375,#376,#377,#378,#379,#380,
#381,#382,#383,#384,#385,#386,#387,#388,#389)),.UNSPECIFIED.,.T.,.F.,
.F.) B_SPLINE_SURFACE_WITH_KNOTS((4,3,4),(4,1,1,1,1,1,1,1,1,1,1,1,1,1,1,1,1,1,1,1,1,1,1,1,1,1,1,
1,1,1,1,1,1,1,1,1,1,1,1,1,1,1,1,1,1,1,1,1,1,1,4),(0.,0.5,1.),(0.,0.0156173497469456,
0.0312853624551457,0.046931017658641,0.0625669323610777,0.0833983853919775,0.104228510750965,
0.125057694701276,0.145888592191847,0.166719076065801,0.187548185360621,0.208378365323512,
0.229209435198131,0.250038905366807,0.270868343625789,0.29169940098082,0.312529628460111,
0.333358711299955,0.354189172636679,0.375020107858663,0.395849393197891,0.416679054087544,
0.437510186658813,0.458340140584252,0.479169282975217,0.499999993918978,0.520830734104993,
0.541659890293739,0.562489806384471,0.583320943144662,0.604150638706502,0.624979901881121,
0.64581081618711,0.666641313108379,0.687470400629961,0.70830058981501,0.729131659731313,
0.749961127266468,0.770790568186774,0.791621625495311,0.812451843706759,0.833280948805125,
0.854111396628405,0.874942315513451,0.895771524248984,0.916601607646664,0.937433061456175,
0.953068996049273,0.968714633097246,0.984382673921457,1.),
.UNSPECIFIED.) GEOMETRIC_REPRESENTATION_ITEM() RATIONAL_B_SPLINE_SURFACE(((1.,1.,1.,1.,1.,1.,1.,
1.,1.,1.,1.,1.,1.,1.,1.,1.,1.,1.,1.,1.,1.,1.,1.,1.,1.,1.,1.,1.,1.,1.,1.,1.,1.,1.,1.,1.,1.,1.,1.,
1.,1.,1.,1.,1.,1.,1.,1.,1.,1.,1.,1.,1.,1.),(0.333333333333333,0.333333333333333,
0.333333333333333,0.333333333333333,0.333333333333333,0.333333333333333,0.333333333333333,
0.333333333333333,0.333333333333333,0.333333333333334,0.333333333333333,0.333333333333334,
0.333333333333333,0.333333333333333,0.333333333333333,0.333333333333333,0.333333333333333,
0.333333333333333,0.333333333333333,0.333333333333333,0.333333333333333,0.333333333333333,
0.333333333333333,0.333333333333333,0.333333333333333,0.333333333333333,0.333333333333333,
0.333333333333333,0.333333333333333,0.333333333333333,0.333333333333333,0.333333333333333,
0.333333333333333,0.333333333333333,0.333333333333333,0.333333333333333,0.333333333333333,
0.333333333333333,0.333333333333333,0.333333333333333,0.333333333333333,0.333333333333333,
0.333333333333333,0.333333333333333,0.333333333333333,0.333333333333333,0.333333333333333,
0.333333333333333,0.333333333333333,0.333333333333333,0.333333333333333,0.333333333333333,
0.333333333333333),(0.333333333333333,0.333333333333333,0.333333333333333,0.333333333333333,
0.333333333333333,0.333333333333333,0.333333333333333,0.333333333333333,0.333333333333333,
0.333333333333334,0.333333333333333,0.333333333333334,0.333333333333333,0.333333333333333,
0.333333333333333,0.333333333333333,0.333333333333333,0.333333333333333,0.333333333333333,
0.333333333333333,0.333333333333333,0.333333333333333,0.333333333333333,0.333333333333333,
0.333333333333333,0.333333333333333,0.333333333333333,0.333333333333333,0.333333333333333,
0.333333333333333,0.333333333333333,0.333333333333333,0.333333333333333,0.333333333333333,
0.333333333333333,0.333333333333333,0.333333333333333,0.333333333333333,0.333333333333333,
0.333333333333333,0.333333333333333,0.333333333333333,0.333333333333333,0.333333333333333,
0.333333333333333,0.333333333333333,0.333333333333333,0.333333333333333,0.333333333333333,
0.333333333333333,0.333333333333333,0.333333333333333,0.333333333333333),(1.,1.,1.,1.,1.,1.,1.,
1.,1.,1.,1.,1.,1.,1.,1.,1.,1.,1.,1.,1.,1.,1.,1.,1.,1.,1.,1.,1.,1.,1.,1.,1.,1.,1.,1.,1.,1.,1.,1.,
1.,1.,1.,1.,1.,1.,1.,1.,1.,1.,1.,1.,1.,1.),(0.333333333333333,0.333333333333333,
0.333333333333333,0.333333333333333,0.333333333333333,0.333333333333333,0.333333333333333,
0.333333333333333,0.333333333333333,0.333333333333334,0.333333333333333,0.333333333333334,
0.333333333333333,0.333333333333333,0.333333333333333,0.333333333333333,0.333333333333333,
0.333333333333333,0.333333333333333,0.333333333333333,0.333333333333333,0.333333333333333,
0.333333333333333,0.333333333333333,0.333333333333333,0.333333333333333,0.333333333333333,
0.333333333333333,0.333333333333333,0.333333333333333,0.333333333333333,0.333333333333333,
0.333333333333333,0.333333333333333,0.333333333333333,0.333333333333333,0.333333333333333,
0.333333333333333,0.333333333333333,0.333333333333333,0.333333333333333,0.333333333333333,
0.333333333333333,0.333333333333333,0.333333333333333,0.333333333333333,0.333333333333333,
0.333333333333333,0.333333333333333,0.333333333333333,0.333333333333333,0.333333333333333,
0.333333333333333),(0.333333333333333,0.333333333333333,0.333333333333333,0.333333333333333,
0.333333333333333,0.333333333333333,0.333333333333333,0.333333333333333,0.333333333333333,
0.333333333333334,0.333333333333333,0.333333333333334,0.333333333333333,0.333333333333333,
0.333333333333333,0.333333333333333,0.333333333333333,0.333333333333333,0.333333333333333,
0.333333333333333,0.333333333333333,0.333333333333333,0.333333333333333,0.333333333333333,
0.333333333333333,0.333333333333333,0.333333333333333,0.333333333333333,0.333333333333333,
0.333333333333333,0.333333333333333,0.333333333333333,0.333333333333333,0.333333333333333,
0.333333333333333,0.333333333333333,0.333333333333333,0.333333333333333,0.333333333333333,
0.333333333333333,0.333333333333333,0.333333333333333,0.333333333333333,0.333333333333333,
0.333333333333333,0.333333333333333,0.333333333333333,0.333333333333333,0.333333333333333,
0.333333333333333,0.333333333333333,0.333333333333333,0.333333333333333),(1.,1.,1.,1.,1.,1.,1.,
1.,1.,1.,1.,1.,1.,1.,1.,1.,1.,1.,1.,1.,1.,1.,1.,1.,1.,1.,1.,1.,1.,1.,1.,1.,1.,1.,1.,1.,1.,1.,1.,
1.,1.,1.,1.,1.,1.,1.,1.,1.,1.,1.,1.,1.,1.))) REPRESENTATION_ITEM('') SURFACE());
#391=CARTESIAN_POINT('',(15.,4.20067276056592E-13,9.99999999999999));
#392=DIRECTION('',(-5.48076765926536E-06,-0.999999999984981,-2.8310986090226E-10));
#393=DIRECTION('',(0.999999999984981,-5.48076765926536E-06,0.));
#394=AXIS2_PLACEMENT_3D('',#391,#392,#393);
#395=CIRCLE('',#394,1.5);
#396=CARTESIAN_POINT('',(16.4999999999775,-8.22115106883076E-06,9.99999999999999));
#397=VERTEX_POINT('',#396);
#398=EDGE_CURVE('E36',#397,#397,#395,.T.);
#399=CARTESIAN_POINT('',(15.,0.,0.));
#400=DIRECTION('',(0.,1.,0.));
#401=DIRECTION('',(0.,0.,1.));
#402=AXIS2_PLACEMENT_3D('',#399,#400,#401);
#403=CIRCLE('',#402,1.5);
#404=CARTESIAN_POINT('',(13.5017772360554,0.,-0.0729969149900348));
#405=VERTEX_POINT('',#404);
#406=CARTESIAN_POINT('',(16.4982227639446,0.,-0.0729969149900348));
#407=VERTEX_POINT('',#406);
#408=EDGE_CURVE('E62',#405,#407,#403,.T.);
#409=CARTESIAN_POINT('',(16.498222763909,6.49755260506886E-10,-0.0729969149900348));
#410=CARTESIAN_POINT('',(16.4907887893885,0.123920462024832,-0.0729969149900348));
#411=CARTESIAN_POINT('',(16.4833194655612,0.247840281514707,-0.0729969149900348));
#412=CARTESIAN_POINT('',(16.4678983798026,0.49579967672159,-0.0729969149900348));
#413=CARTESIAN_POINT('',(16.459946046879,0.619839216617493,-0.0729969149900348));
#414=CARTESIAN_POINT('',(16.4431574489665,0.86794490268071,-0.0729969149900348));
#415=CARTESIAN_POINT('',(16.4343205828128,0.992011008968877,-0.0729969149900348));
#416=CARTESIAN_POINT('',(16.4153582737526,1.24007524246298,-0.0729969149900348));
#417=CARTESIAN_POINT('',(16.4052325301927,1.36407334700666,-0.0729969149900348));
#418=CARTESIAN_POINT('',(16.3832711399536,1.61207149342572,-0.0729969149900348));
#419=CARTESIAN_POINT('',(16.3714334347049,1.73607135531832,-0.0729969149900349));
#420=CARTESIAN_POINT('',(16.3456498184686,1.98381607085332,-0.0729969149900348));
#421=CARTESIAN_POINT('',(16.3317045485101,2.10756099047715,-0.0729969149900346));
#422=CARTESIAN_POINT('',(16.3012931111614,2.3547029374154,-0.0729969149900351));
#423=CARTESIAN_POINT('',(16.2848277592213,2.47810006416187,-0.0729969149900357));
#424=CARTESIAN_POINT('',(16.2489811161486,2.72445608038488,-0.072996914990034));
#425=CARTESIAN_POINT('',(16.22960022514,2.84741502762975,-0.0729969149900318));
#426=CARTESIAN_POINT('',(16.1859132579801,3.10185245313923,-0.0729969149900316));
#427=CARTESIAN_POINT('',(16.1613486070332,3.23328691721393,-0.072996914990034));
#428=CARTESIAN_POINT('',(16.1081044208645,3.49532536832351,-0.0729969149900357));
#429=CARTESIAN_POINT('',(16.0794246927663,3.62592931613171,-0.0729969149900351));
#430=CARTESIAN_POINT('',(16.0181658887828,3.88631586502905,-0.0729969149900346));
#431=CARTESIAN_POINT('',(15.9855840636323,4.01609781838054,-0.0729969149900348));
#432=CARTESIAN_POINT('',(15.9166850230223,4.27466188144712,-0.0729969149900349));
#433=CARTESIAN_POINT('',(15.8803678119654,4.40344399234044,-0.0729969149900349));
#434=CARTESIAN_POINT('',(15.7660374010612,4.78827521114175,-0.0729969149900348));
#435=CARTESIAN_POINT('',(15.6826602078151,5.04274694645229,-0.0729969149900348));
#436=CARTESIAN_POINT('',(15.5028150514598,5.54703992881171,-0.0729969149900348));
#437=CARTESIAN_POINT('',(15.4063451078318,5.79686046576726,-0.0729969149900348));
#438=CARTESIAN_POINT('',(15.2526921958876,6.16782372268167,-0.0729969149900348));
#439=CARTESIAN_POINT('',(15.1999873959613,6.29084138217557,-0.0729969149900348));
#440=CARTESIAN_POINT('',(15.0916810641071,6.535594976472,-0.0729969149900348));
#441=CARTESIAN_POINT('',(15.0360795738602,6.65733092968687,-0.0729969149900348));
#442=CARTESIAN_POINT('',(14.8649260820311,7.02046837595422,-0.0729969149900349));
#443=CARTESIAN_POINT('',(14.745015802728,7.25982181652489,-0.072996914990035));
#444=CARTESIAN_POINT('',(14.4204043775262,7.87001326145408,-0.0729969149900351));
#445=CARTESIAN_POINT('',(14.2069790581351,8.23628006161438,-0.0729969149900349));
#446=CARTESIAN_POINT('',(13.8654552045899,8.77191782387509,-0.0729969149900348));
#447=CARTESIAN_POINT('',(13.7480348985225,8.94818945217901,-0.0729969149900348));
#448=CARTESIAN_POINT('',(13.5061266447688,9.29581344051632,-0.0729969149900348));
#449=CARTESIAN_POINT('',(13.3816388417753,9.46716590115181,-0.0729969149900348));
#450=CARTESIAN_POINT('',(12.9982577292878,9.97302903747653,-0.0729969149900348));
#451=CARTESIAN_POINT('',(12.7291219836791,10.2998545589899,-0.0729969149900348));
#452=CARTESIAN_POINT('',(12.1655288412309,10.9307559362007,-0.0729969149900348));
#453=CARTESIAN_POINT('',(11.8710772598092,11.2348369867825,-0.0729969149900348));
#454=CARTESIAN_POINT('',(11.4060094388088,11.6779004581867,-0.0729969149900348));
#455=CARTESIAN_POINT('',(11.2439449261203,11.8259492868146,-0.0729969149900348));
#456=CARTESIAN_POINT('',(10.9137963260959,12.1151093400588,-0.0729969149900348));
#457=CARTESIAN_POINT('',(10.7457137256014,12.25622225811,-0.0729969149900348));
#458=CARTESIAN_POINT('',(10.4037765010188,12.5312962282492,-0.0729969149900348));
#459=CARTESIAN_POINT('',(10.2299215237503,12.6652568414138,-0.0729969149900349));
#460=CARTESIAN_POINT('',(9.87670898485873,12.9257826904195,-0.0729969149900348));
#461=CARTESIAN_POINT('',(9.69735011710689,13.0523461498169,-0.0729969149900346));
#462=CARTESIAN_POINT('',(9.15706196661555,13.4167697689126,-0.072996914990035));
#463=CARTESIAN_POINT('',(8.78861274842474,13.6436295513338,-0.0729969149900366));
#464=CARTESIAN_POINT('',(8.03377978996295,14.0654975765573,-0.0729969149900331));
#465=CARTESIAN_POINT('',(7.64738966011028,14.2604943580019,-0.0729969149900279));
#466=CARTESIAN_POINT('',(6.85875035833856,14.6173143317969,-0.0729969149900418));
#467=CARTESIAN_POINT('',(6.4564741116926,14.7790776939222,-0.072996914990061));
#468=CARTESIAN_POINT('',(5.63954355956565,15.0675365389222,-0.0729969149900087));
#469=CARTESIAN_POINT('',(5.22489148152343,15.1942382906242,-0.0729969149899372));
#470=CARTESIAN_POINT('',(4.59729042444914,15.356385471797,-0.0729969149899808));
#471=CARTESIAN_POINT('',(4.38783571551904,15.4056693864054,-0.07299691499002));
#472=CARTESIAN_POINT('',(3.9669561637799,15.4949605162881,-0.0729969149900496));
#473=CARTESIAN_POINT('',(3.75553131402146,15.534967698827,-0.07299691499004));
#474=CARTESIAN_POINT('',(3.11876852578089,15.6408653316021,-0.0729969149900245));
#475=CARTESIAN_POINT('',(2.69099499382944,15.6926182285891,-0.0729969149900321));
#476=CARTESIAN_POINT('',(1.8328405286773,15.7568678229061,-0.0729969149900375));
#477=CARTESIAN_POINT('',(1.40246240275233,15.7694011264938,-0.0729969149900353));
#478=CARTESIAN_POINT('',(0.75777633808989,15.7571392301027,-0.0729969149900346));
#479=CARTESIAN_POINT('',(0.543094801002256,15.7478826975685,-0.0729969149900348));
#480=CARTESIAN_POINT('',(0.11448225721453,15.718580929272,-0.0729969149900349));
#481=CARTESIAN_POINT('',(-0.099448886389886,15.6985377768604,-0.0729969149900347));
#482=CARTESIAN_POINT('',(-0.504249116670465,15.6497115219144,-0.0729969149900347));
#483=CARTESIAN_POINT('',(-0.695251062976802,15.6220245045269,-0.0729969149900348));
#484=CARTESIAN_POINT('',(-1.07569935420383,15.5568706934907,-0.0729969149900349));
#485=CARTESIAN_POINT('',(-1.26514498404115,15.5193996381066,-0.0729969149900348));
#486=CARTESIAN_POINT('',(-1.54727646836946,15.4550801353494,-0.0729969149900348));
#487=CARTESIAN_POINT('',(-1.64090285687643,15.4323107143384,-0.0729969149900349));
#488=CARTESIAN_POINT('',(-1.82738830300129,15.3838312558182,-0.0729969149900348));
#489=CARTESIAN_POINT('',(-1.92024743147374,15.3581214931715,-0.0729969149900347));
#490=CARTESIAN_POINT('',(-2.1049068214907,15.3034528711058,-0.0729969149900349));
#491=CARTESIAN_POINT('',(-2.19670804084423,15.274497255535,-0.0729969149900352));
#492=CARTESIAN_POINT('',(-2.37901720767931,15.2127940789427,-0.0729969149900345));
#493=CARTESIAN_POINT('',(-2.46952553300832,15.1800476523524,-0.0729969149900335));
#494=CARTESIAN_POINT('',(-2.60379209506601,15.1273613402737,-0.072996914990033));
#495=CARTESIAN_POINT('',(-2.64825845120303,15.1092229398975,-0.0729969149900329));
#496=CARTESIAN_POINT('',(-2.73660724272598,15.0715185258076,-0.0729969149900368));
#497=CARTESIAN_POINT('',(-2.78048944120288,15.0519519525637,-0.0729969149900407));
#498=CARTESIAN_POINT('',(-2.86733620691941,15.0111081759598,-0.072996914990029));
#499=CARTESIAN_POINT('',(-2.91030260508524,14.9898348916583,-0.0729969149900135));
#500=CARTESIAN_POINT('',(-2.99499694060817,14.9449915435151,-0.0729969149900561));
#501=CARTESIAN_POINT('',(-3.03672591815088,14.9214234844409,-0.0729969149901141));
#502=CARTESIAN_POINT('',(-3.10445387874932,14.8792767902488,-0.0729969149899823));
#503=CARTESIAN_POINT('',(-3.131043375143,14.861668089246,-0.0729969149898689));
#504=CARTESIAN_POINT('',(-3.16970928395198,14.8335123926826,-0.072996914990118));
#505=CARTESIAN_POINT('',(-3.18240804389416,14.823825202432,-0.0729969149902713));
#506=CARTESIAN_POINT('',(-3.20719980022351,14.803710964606,-0.0729969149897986));
#507=CARTESIAN_POINT('',(-3.2192932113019,14.7932844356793,-0.0729969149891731));
#508=CARTESIAN_POINT('',(-3.24265479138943,14.7713482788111,-0.0729969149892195));
#509=CARTESIAN_POINT('',(-3.25391556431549,14.7598306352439,-0.0729969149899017));
#510=CARTESIAN_POINT('',(-3.27478581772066,14.7354504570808,-0.0729969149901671));
#511=CARTESIAN_POINT('',(-3.28440577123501,14.7225973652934,-0.0729969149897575));
#512=CARTESIAN_POINT('',(-3.29827559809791,14.6985551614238,-0.0729969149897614));
#513=CARTESIAN_POINT('',(-3.30327355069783,14.6878395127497,-0.0729969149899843));
#514=CARTESIAN_POINT('',(-3.30833047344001,14.6709064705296,-0.0729969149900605));
#515=CARTESIAN_POINT('',(-3.30960959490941,14.6650687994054,-0.0729969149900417));
#516=CARTESIAN_POINT('',(-3.31104141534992,14.653265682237,-0.072996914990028));
#517=CARTESIAN_POINT('',(-3.31119878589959,14.6473008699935,-0.072996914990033));
#518=CARTESIAN_POINT('',(-3.31025048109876,14.6359928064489,-0.0729969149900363));
#519=CARTESIAN_POINT('',(-3.30925404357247,14.6306408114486,-0.0729969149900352));
#520=CARTESIAN_POINT('',(-3.30619598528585,14.6202492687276,-0.0729969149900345));
#521=CARTESIAN_POINT('',(-3.30413344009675,14.6152099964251,-0.0729969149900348));
#522=CARTESIAN_POINT('',(-3.2962750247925,14.6001699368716,-0.0729969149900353));
#523=CARTESIAN_POINT('',(-3.28889552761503,14.5910067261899,-0.072996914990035));
#524=CARTESIAN_POINT('',(-3.27342900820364,14.5760486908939,-0.0729969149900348));
#525=CARTESIAN_POINT('',(-3.26559169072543,14.569960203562,-0.0729969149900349));
#526=CARTESIAN_POINT('',(-3.24914312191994,14.5588984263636,-0.0729969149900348));
#527=CARTESIAN_POINT('',(-3.2405296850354,14.5539284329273,-0.0729969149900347));
#528=CARTESIAN_POINT('',(-3.21755358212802,14.5420702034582,-0.0729969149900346));
#529=CARTESIAN_POINT('',(-3.20286293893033,14.5358384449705,-0.0729969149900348));
#530=CARTESIAN_POINT('',(-3.17301552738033,14.5247206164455,-0.0729969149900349));
#531=CARTESIAN_POINT('',(-3.1578589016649,14.5198341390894,-0.0729969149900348));
#532=CARTESIAN_POINT('',(-3.12717893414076,14.5109519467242,-0.0729969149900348));
#533=CARTESIAN_POINT('',(-3.11165379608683,14.5069625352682,-0.0729969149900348));
#534=CARTESIAN_POINT('',(-3.08045584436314,14.4996604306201,-0.0729969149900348));
#535=CARTESIAN_POINT('',(-3.06478309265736,14.4963474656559,-0.0729969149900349));
#536=CARTESIAN_POINT('',(-3.01244054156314,14.4861443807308,-0.0729969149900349));
#537=CARTESIAN_POINT('',(-2.97555885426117,14.4803545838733,-0.0729969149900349));
#538=CARTESIAN_POINT('',(-2.90158282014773,14.4703122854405,-0.0729969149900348));
#539=CARTESIAN_POINT('',(-2.86448835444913,14.4660607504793,-0.0729969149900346));
#540=CARTESIAN_POINT('',(-2.79014421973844,14.4585474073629,-0.0729969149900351));
#541=CARTESIAN_POINT('',(-2.7528944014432,14.4552870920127,-0.0729969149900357));
#542=CARTESIAN_POINT('',(-2.67834148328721,14.4494344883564,-0.072996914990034));
#543=CARTESIAN_POINT('',(-2.64103837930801,14.446842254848,-0.0729969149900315));
#544=CARTESIAN_POINT('',(-2.52924309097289,14.4397501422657,-0.0729969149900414));
#545=CARTESIAN_POINT('',(-2.45470929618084,14.4359212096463,-0.0729969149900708));
#546=CARTESIAN_POINT('',(-2.30568466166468,14.4290778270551,-0.0729969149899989));
#547=CARTESIAN_POINT('',(-2.23119385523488,14.4260625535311,-0.0729969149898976));
#548=CARTESIAN_POINT('',(-2.08247328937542,14.4203380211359,-0.0729969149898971));
#549=CARTESIAN_POINT('',(-2.00824357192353,14.4176276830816,-0.0729969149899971));
#550=CARTESIAN_POINT('',(-1.85978563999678,14.412176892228,-0.0729969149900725));
#551=CARTESIAN_POINT('',(-1.78555742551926,14.4094364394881,-0.0729969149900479));
#552=CARTESIAN_POINT('',(-1.56288659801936,14.4008301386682,-0.0729969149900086));
#553=CARTESIAN_POINT('',(-1.41445765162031,14.394579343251,-0.0729969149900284));
#554=CARTESIAN_POINT('',(-1.11767090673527,14.3799647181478,-0.0729969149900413));
#555=CARTESIAN_POINT('',(-0.969313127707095,14.3716004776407,-0.0729969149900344));
#556=CARTESIAN_POINT('',(-0.672771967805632,14.3521475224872,-0.0729969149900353));
#557=CARTESIAN_POINT('',(-0.524588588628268,14.3410587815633,-0.0729969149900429));
#558=CARTESIAN_POINT('',(-0.228496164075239,14.3157447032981,-0.0729969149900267));
#559=CARTESIAN_POINT('',(-0.080587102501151,14.3015195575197,-0.0729969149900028));
#560=CARTESIAN_POINT('',(0.214860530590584,14.2696509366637,-0.0729969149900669));
#561=CARTESIAN_POINT('',(0.362399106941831,14.2520075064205,-0.072996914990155));
#562=CARTESIAN_POINT('',(0.804374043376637,14.1936694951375,-0.0729969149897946));
#563=CARTESIAN_POINT('',(1.09810840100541,14.1475722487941,-0.0729969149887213));
#564=CARTESIAN_POINT('',(1.82847981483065,14.0132252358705,-0.0729969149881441));
#565=CARTESIAN_POINT('',(2.26342677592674,13.9154160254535,-0.072996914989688));
#566=CARTESIAN_POINT('',(2.90852311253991,13.7417423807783,-0.0729969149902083));
#567=CARTESIAN_POINT('',(3.12237883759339,13.67934186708,-0.0729969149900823));
#568=CARTESIAN_POINT('',(3.54722137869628,13.5454434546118,-0.0729969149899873));
#569=CARTESIAN_POINT('',(3.75820825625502,13.4739457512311,-0.0729969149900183));
#570=CARTESIAN_POINT('',(4.38604997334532,13.2458330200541,-0.0729969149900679));
#571=CARTESIAN_POINT('',(4.79802264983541,13.0755349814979,-0.0729969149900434));
#572=CARTESIAN_POINT('',(5.60512107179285,12.6991620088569,-0.0729969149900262));
#573=CARTESIAN_POINT('',(6.00025367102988,12.4931018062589,-0.0729969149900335));
#574=CARTESIAN_POINT('',(6.57149197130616,12.1614316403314,-0.0729969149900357));
#575=CARTESIAN_POINT('',(6.75543525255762,12.0491558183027,-0.0729969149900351));
#576=CARTESIAN_POINT('',(7.11810442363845,11.8165769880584,-0.0729969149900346));
#577=CARTESIAN_POINT('',(7.29683167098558,11.6962760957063,-0.0729969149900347));
#578=CARTESIAN_POINT('',(7.8247507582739,11.3236682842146,-0.0729969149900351));
#579=CARTESIAN_POINT('',(8.16576182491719,11.0596086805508,-0.0729969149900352));
#580=CARTESIAN_POINT('',(8.80197431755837,10.520133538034,-0.0729969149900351));
#581=CARTESIAN_POINT('',(9.09871035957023,10.2465178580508,-0.0729969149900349));
#582=CARTESIAN_POINT('',(9.66813459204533,9.6752339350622,-0.0729969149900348));
#583=CARTESIAN_POINT('',(9.94082481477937,9.37756772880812,-0.0729969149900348));
#584=CARTESIAN_POINT('',(10.3302750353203,8.91428345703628,-0.0729969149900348));
#585=CARTESIAN_POINT('',(10.4569442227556,8.75689234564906,-0.0729969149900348));
#586=CARTESIAN_POINT('',(10.7033977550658,8.43685184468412,-0.0729969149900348));
#587=CARTESIAN_POINT('',(10.8231837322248,8.27420371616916,-0.0729969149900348));
#588=CARTESIAN_POINT('',(11.0556048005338,7.9439124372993,-0.0729969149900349));
#589=CARTESIAN_POINT('',(11.1682410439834,7.77627009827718,-0.0729969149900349));
#590=CARTESIAN_POINT('',(11.3861005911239,7.43624339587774,-0.0729969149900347));
#591=CARTESIAN_POINT('',(11.4913235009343,7.26385878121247,-0.0729969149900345));
#592=CARTESIAN_POINT('',(11.7936246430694,6.7437901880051,-0.0729969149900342));
#593=CARTESIAN_POINT('',(11.9798093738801,6.38966586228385,-0.0729969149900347));
#594=CARTESIAN_POINT('',(12.2367692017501,5.84793689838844,-0.0729969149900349));
#595=CARTESIAN_POINT('',(12.3187342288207,5.66552051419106,-0.0729969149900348));
#596=CARTESIAN_POINT('',(12.4360856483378,5.38950879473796,-0.0729969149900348));
#597=CARTESIAN_POINT('',(12.4742709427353,5.29710480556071,-0.0729969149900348));
#598=CARTESIAN_POINT('',(12.5487750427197,5.11154737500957,-0.0729969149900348));
#599=CARTESIAN_POINT('',(12.5850937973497,5.01839391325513,-0.0729969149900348));
#600=CARTESIAN_POINT('',(12.6911155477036,4.73789035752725,-0.0729969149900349));
#601=CARTESIAN_POINT('',(12.7579146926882,4.54942514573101,-0.0729969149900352));
#602=CARTESIAN_POINT('',(12.883076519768,4.16974305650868,-0.0729969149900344));
#603=CARTESIAN_POINT('',(12.9414389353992,3.97852609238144,-0.0729969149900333));
#604=CARTESIAN_POINT('',(13.1026213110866,3.40150532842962,-0.0729969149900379));
#605=CARTESIAN_POINT('',(13.1917950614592,3.01165981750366,-0.0729969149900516));
#606=CARTESIAN_POINT('',(13.2843336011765,2.47418739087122,-0.0729969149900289));
#607=CARTESIAN_POINT('',(13.306270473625,2.32957315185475,-0.0729969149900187));
#608=CARTESIAN_POINT('',(13.3453889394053,2.03964434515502,-0.072996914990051));
#609=CARTESIAN_POINT('',(13.3625686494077,1.8943295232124,-0.0729969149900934));
#610=CARTESIAN_POINT('',(13.3931411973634,1.60323279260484,-0.0729969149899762));
#611=CARTESIAN_POINT('',(13.4065319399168,1.4574506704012,-0.0729969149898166));
#612=CARTESIAN_POINT('',(13.4304934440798,1.16588161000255,-0.0729969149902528));
#613=CARTESIAN_POINT('',(13.4410684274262,1.02009501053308,-0.0729969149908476));
#614=CARTESIAN_POINT('',(13.4604052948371,0.728494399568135,-0.0729969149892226));
#615=CARTESIAN_POINT('',(13.4691682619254,0.582680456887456,-0.0729969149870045));
#616=CARTESIAN_POINT('',(13.4858540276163,0.291241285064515,-0.0729969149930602));
#617=CARTESIAN_POINT('',(13.4937781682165,0.145616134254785,-0.072996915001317));
#618=CARTESIAN_POINT('',(13.5017772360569,0.,-0.0729969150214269));
#619=B_SPLINE_CURVE_WITH_KNOTS('',3,(#409,#410,#411,#412,#413,#414,#415,#416,#417,#418,#419,
#420,#421,#422,#423,#424,#425,#426,#427,#428,#429,#430,#431,#432,#433,#434,#435,#436,#437,#438,
#439,#440,#441,#442,#443,#444,#445,#446,#447,#448,#449,#450,#451,#452,#453,#454,#455,#456,#457,
#458,#459,#460,#461,#462,#463,#464,#465,#466,#467,#468,#469,#470,#471,#472,#473,#474,#475,#476,
#477,#478,#479,#480,#481,#482,#483,#484,#485,#486,#487,#488,#489,#490,#491,#492,#493,#494,#495,
#496,#497,#498,#499,#500,#501,#502,#503,#504,#505,#506,#507,#508,#509,#510,#511,#512,#513,#514,
#515,#516,#517,#518,#519,#520,#521,#522,#523,#524,#525,#526,#527,#528,#529,#530,#531,#532,#533,
#534,#535,#536,#537,#538,#539,#540,#541,#542,#543,#544,#545,#546,#547,#548,#549,#550,#551,#552,
#553,#554,#555,#556,#557,#558,#559,#560,#561,#562,#563,#564,#565,#566,#567,#568,#569,#570,#571,
#572,#573,#574,#575,#576,#577,#578,#579,#580,#581,#582,#583,#584,#585,#586,#587,#588,#589,#590,
#591,#592,#593,#594,#595,#596,#597,#598,#599,#600,#601,#602,#603,#604,#605,#606,#607,#608,#609,
#610,#611,#612,#613,#614,#615,#616,#617,#618),.UNSPECIFIED.,.F.,.F.,(4,2,2,2,2,2,2,2,2,2,2,2,2,
2,2,2,2,2,2,2,2,2,2,2,2,2,2,2,2,2,2,2,2,2,2,2,2,2,2,2,2,2,2,2,2,2,2,2,2,2,2,2,2,2,2,2,2,2,2,2,2,
2,2,2,2,2,2,2,2,2,2,2,2,2,2,2,2,2,2,2,2,2,2,2,2,2,2,2,2,2,2,2,2,2,2,2,2,2,2,2,2,2,2,2,4),(0.,
0.37243215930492,0.745313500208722,1.1184500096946,1.49167371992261,1.8653500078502,
2.23891286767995,2.61235510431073,2.98574613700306,3.3868118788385,3.78789642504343,
4.18926524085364,4.59063358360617,5.39356196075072,6.19661193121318,6.59807836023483,
6.99953901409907,7.80238780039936,9.07260623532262,9.70786133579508,10.3431034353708,
11.611781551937,12.8801690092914,13.5385264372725,14.1967223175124,14.8549585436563,
15.5133522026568,16.8097722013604,18.1066575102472,19.405857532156,20.7048251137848,
21.3501695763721,21.9955163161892,23.2863723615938,24.5760232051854,25.2204459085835,
25.8647441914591,26.4435209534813,27.0225502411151,27.3115787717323,27.6005803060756,
27.8892955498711,28.1779246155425,28.3219768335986,28.4660857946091,28.6098728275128,
28.7535353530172,28.8491179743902,28.8970138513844,28.9448764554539,28.9931229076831,
29.041048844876,29.0761650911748,29.0940100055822,29.1117805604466,29.1279972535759,
29.1442280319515,29.178823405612,29.2085008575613,29.2382646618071,29.2860200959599,
29.3337610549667,29.3818276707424,29.4298749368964,29.5418033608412,29.6538019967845,
29.7659684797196,29.8781441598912,30.1020269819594,30.325682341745,30.5485194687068,
30.7713561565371,31.2170290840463,31.6627887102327,32.1085526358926,32.5542893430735,
33.0000202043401,33.891665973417,35.2274010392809,35.8955502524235,36.5636851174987,
37.8992220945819,39.2342102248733,39.8805293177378,40.5266786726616,41.8186943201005,
43.0282647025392,44.2377327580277,44.8436777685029,45.4494784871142,46.0551813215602,
46.6609163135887,47.8595061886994,48.4593317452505,48.7592587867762,49.0591940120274,
49.6588299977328,50.2584849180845,51.4556422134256,51.8943790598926,52.3332893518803,
52.7724419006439,53.2109322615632,53.6491597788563,54.0866752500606),.UNSPECIFIED.);
#620=EDGE_CURVE('E47',#407,#405,#619,.T.);
#621=ORIENTED_EDGE('',*,*,#398,.T.);
#622=EDGE_LOOP('',(#621));
#623=FACE_BOUND('',#622,.T.);
#624=ORIENTED_EDGE('',*,*,#408,.T.);
#625=ORIENTED_EDGE('',*,*,#620,.T.);
#626=EDGE_LOOP('',(#624,#625));
#627=FACE_BOUND('',#626,.T.);
#628=ADVANCED_FACE('F28',(#623,#627),#390,.T.);
#629=CARTESIAN_POINT('',(0.,0.,0.));
#630=DIRECTION('',(0.,0.,1.));
#631=DIRECTION('',(1.,0.,0.));
#632=AXIS2_PLACEMENT_3D('',#629,#630,#631);
#633=TOROIDAL_SURFACE('',#632,15.,1.5);
#634=CARTESIAN_POINT('',(0.,0.,-0.0729969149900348));
#635=DIRECTION('',(0.,0.,-1.));
#636=DIRECTION('',(-1.,0.,0.));
#637=AXIS2_PLACEMENT_3D('',#634,#635,#636);
#638=CIRCLE('',#637,16.4982227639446);
#639=CARTESIAN_POINT('',(-8.24911138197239,-14.2878800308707,-0.0729969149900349));
#640=VERTEX_POINT('',#639);
#641=EDGE_CURVE('E43',#407,#640,#638,.T.);
#642=ORIENTED_EDGE('',*,*,#641,.F.);
#643=ORIENTED_EDGE('',*,*,#408,.F.);
#644=CARTESIAN_POINT('',(0.,0.,-0.0729969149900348));
#645=DIRECTION('',(0.,0.,1.));
#646=DIRECTION('',(1.,0.,0.));
#647=AXIS2_PLACEMENT_3D('',#644,#645,#646);
#648=CIRCLE('',#647,13.5017772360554);
#649=CARTESIAN_POINT('',(-6.75088861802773,-11.6928820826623,-0.0729969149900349));
#650=VERTEX_POINT('',#649);
#651=EDGE_CURVE('E53',#650,#405,#648,.T.);
#652=ORIENTED_EDGE('',*,*,#651,.F.);
#653=CARTESIAN_POINT('',(-7.50000000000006,-12.9903810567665,0.));
#654=DIRECTION('',(-0.866025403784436,0.500000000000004,0.));
#655=DIRECTION('',(0.,0.,-1.));
#656=AXIS2_PLACEMENT_3D('',#653,#654,#655);
#657=CIRCLE('',#656,1.5);
#658=EDGE_CURVE('E60',#640,#650,#657,.T.);
#659=ORIENTED_EDGE('',*,*,#658,.F.);
#660=EDGE_LOOP('',(#642,#643,#652,#659));
#661=FACE_BOUND('',#660,.T.);
#662=ADVANCED_FACE('F59',(#661),#633,.T.);
#663=CARTESIAN_POINT('',(-7.50000000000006,-12.9903810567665,0.));
#664=DIRECTION('',(-0.866025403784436,0.500000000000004,0.));
#665=DIRECTION('',(0.,0.,-1.));
#666=AXIS2_PLACEMENT_3D('',#663,#664,#665);
#667=PLANE('',#666);
#668=ORIENTED_EDGE('',*,*,#658,.T.);
#669=DIRECTION('',(-0.500000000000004,-0.866025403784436,0.));
#670=VECTOR('',#669,1.);
#671=CARTESIAN_POINT('',(-7.50000000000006,-12.9903810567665,-0.0729969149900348));
#672=LINE('',#671,#670);
#673=EDGE_CURVE('E11',#650,#640,#672,.T.);
#674=ORIENTED_EDGE('',*,*,#673,.T.);
#675=EDGE_LOOP('',(#668,#674));
#676=FACE_BOUND('',#675,.T.);
#677=ADVANCED_FACE('F64',(#676),#667,.T.);
#678=CARTESIAN_POINT('',(15.0001549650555,-4.24242608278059E-10,8.50000000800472));
#679=DIRECTION('',(-5.48076765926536E-06,-0.999999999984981,-2.8310986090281E-10));
#680=DIRECTION('',(0.999999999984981,-5.48076765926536E-06,0.));
#681=AXIS2_PLACEMENT_3D('',#678,#679,#680);
#682=PLANE('',#681);
#683=ORIENTED_EDGE('',*,*,#398,.F.);
#684=EDGE_LOOP('',(#683));
#685=FACE_BOUND('',#684,.T.);
#686=ADVANCED_FACE('F30',(#685),#682,.F.);
#687=CARTESIAN_POINT('',(-78.6714053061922,20.5732977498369,-0.0729969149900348));
#688=DIRECTION('',(0.,0.,-1.));
#689=DIRECTION('',(-1.,0.,0.));
#690=AXIS2_PLACEMENT_3D('',#687,#688,#689);
#691=PLANE('',#690);
#692=ORIENTED_EDGE('',*,*,#620,.F.);
#693=ORIENTED_EDGE('',*,*,#641,.T.);
#694=ORIENTED_EDGE('',*,*,#673,.F.);
#695=ORIENTED_EDGE('',*,*,#651,.T.);
#696=EDGE_LOOP('',(#692,#693,#694,#695));
#697=FACE_BOUND('',#696,.T.);
#698=ADVANCED_FACE('F52',(#697),#691,.T.);
#699=CLOSED_SHELL('',(#628,#662,#677,#686,#698));
#700=MANIFOLD_SOLID_BREP('B2',#699);
#701=ADVANCED_BREP_SHAPE_REPRESENTATION('',(#18,#700),#14);
#702=SHAPE_DEFINITION_REPRESENTATION(#9,#701);
ENDSEC;
END-ISO-10303-21;
